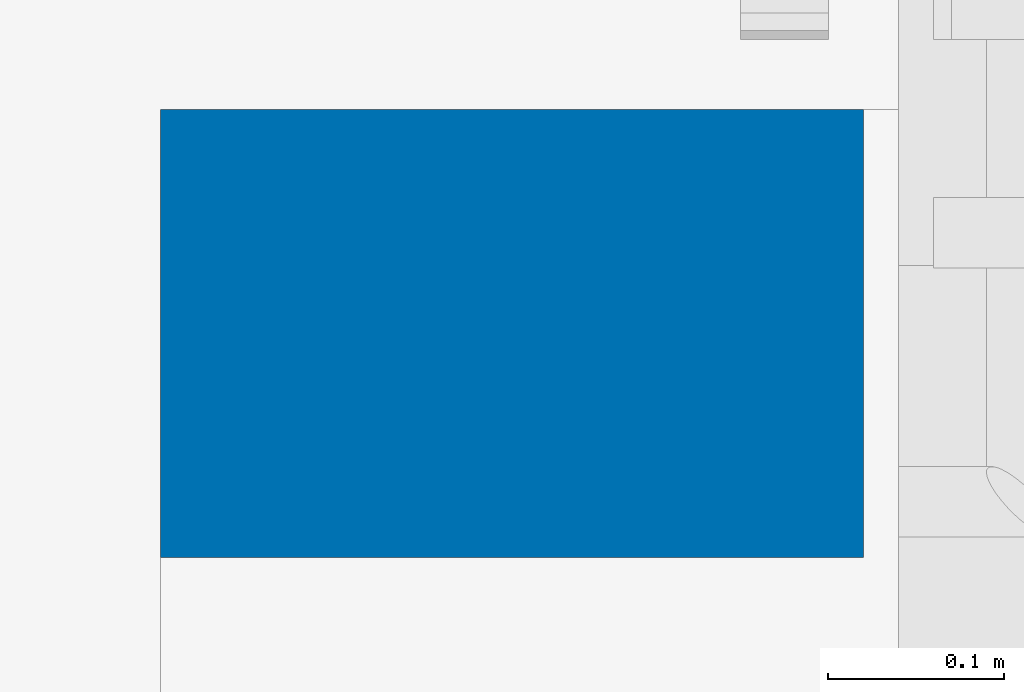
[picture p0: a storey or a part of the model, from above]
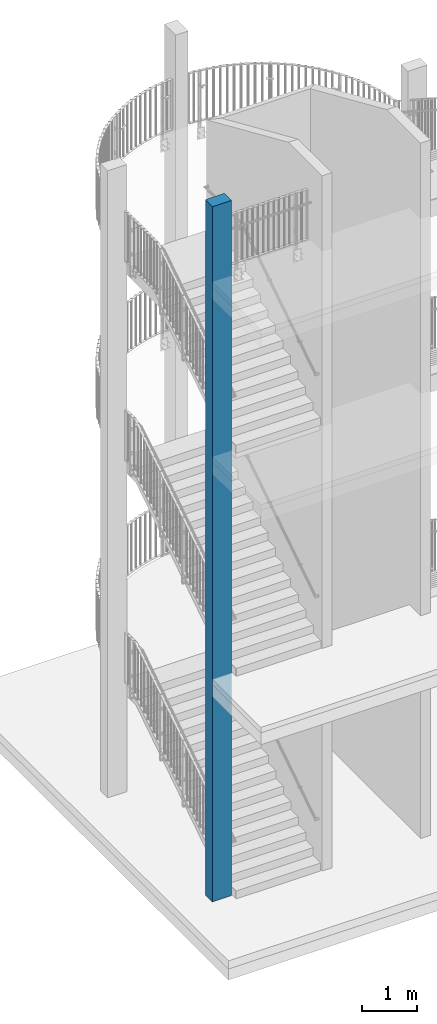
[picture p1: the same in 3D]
Properties of the parts of a building model (IFC2X3)

# File
Description: ViewDefinition[CoordinationView_V2.0]
File name: Treppenhausgel?nder TZ Dresden_ifc2x3.ifc
Time: 2026-07-12T18:13:56
Written by: IFC Toolkit 2.0.26.0
Made in: Advance Steel 2024

# IfcBuildingStorey, Default Storey
In: Struktur 1
Elevation: 0 mm

# IfcBeam: - (91)
In: Default Storey
Material: S235JR
Name | Description = Section | SectionFamily
74 x - | RD12 | Round nach DIN
17 x - | FL50X10 | Flat nach DIN

# IfcBeam: Column
In: Default Storey
Material: C20/25
Pset_BeamCommon - Reference: nicht definiert; Span: 3520 mm; Slope: 0 deg; IsExternal: no; LoadBearing: no

# IfcBeam: Gel?nder (11)
In: Default Storey
Description: FL50X10; Material: S235JR
Pset_BeamCommon - Slope: 0 deg; IsExternal: no; LoadBearing: no
ProfileProperties - SectionFamily: Flat nach DIN; Section: FL50X10
Name | Reference | Span (mm)
Gel?nder | 117 | 312.5
Gel?nder | 76 | 697.496
Gel?nder | 111 | 209.996
Gel?nder | 102 | 214.996
2 x Gel?nder | 66 | 232.5
Gel?nder | 118 | 1225
Gel?nder | 115 | 960.496
2 x Gel?nder | 74 | 177.5
Gel?nder | 99 | 187.5

# IfcBeam: Girder (31)
In: Default Storey
Description: RD40; Material: Buche
Pset_BeamCommon - Slope: 0 deg; IsExternal: no; LoadBearing: no
ProfileProperties - SectionFamily: Round nach DIN; Section: RD40
Name | Reference | Span (mm)
Girder | 7 | 89.6687
Girder | 7 | 89.6743
Girder | 7 | 89.6653
Girder | 23 | 1304.99
Girder | 25 | 489.995
Girder | 26 | 494.994
3 x Girder | 2 | 89.9986
Girder | 41 | 1368
2 x Girder | 4 | 79.6687
Girder | 4 | 79.6743
Girder | 4 | 79.6653
Girder | 45 | 559.998
Girder | 8 | 574.999
Girder | 46 | 1389.99
Girder | 8 | 574.995
Girder | 47 | 579.994
6 x Girder | 1 | 79.9986
Girder | 4 | 79.6709
Girder | 4 | 79.6681
Girder | 59 | 1720
Girder | 12 | 539.999
Girder | 13 | 555
Girder | 11 | 1348

# IfcColumn: - (456)
In: Default Storey
Material: S235JR
Name | Description = Section | SectionFamily
330 x - | RD10 | Round nach DIN
112 x - | FL50X15 | Flat nach DIN
14 x - | FL50X10 | Flat nach DIN

# IfcColumn: Column (5)
In: Default Storey
Material: C20/25
Pset_ColumnCommon - Reference: nicht definiert; Slope: 0 deg; IsExternal: no; LoadBearing: no

# IfcMechanicalFastener: - (199)
In: Default Storey
Name | NominalDiameter (mm) | NominalLength (mm)
50 x  | 12 | 120
99 x  | 8 | 60
50 x  | 12 | 65

# IfcMember: - (29)
In: Default Storey
Description: FL50X10; Material: S235JR
ProfileProperties - SectionFamily: Flat nach DIN; Section: FL50X10

# IfcMember: Gel?nder (22)
In: Default Storey
Description: FL50X10; Material: S235JR
Pset_MemberCommon - Slope: 0 deg; IsExternal: no; LoadBearing: no
ProfileProperties - SectionFamily: Flat nach DIN; Section: FL50X10
Name | Reference | Span (mm)
Gel?nder | 110 | 1275.33
Gel?nder | 68 | 1274.68
Gel?nder | 109 | 959.605
Gel?nder | 108 | 1275.33
Gel?nder | 107 | 163.817
Gel?nder | 73 | 959.118
Gel?nder | 101 | 1274.68
Gel?nder | 100 | 163.735
Gel?nder | 72 | 959.507
Gel?nder | 75 | 1275.2
Gel?nder | 116 | 163.801
Gel?nder | 114 | 953.551
Gel?nder | 105 | 952.585
Gel?nder | 106 | 1092.42
Gel?nder | 97 | 954.135
Gel?nder | 98 | 1088.24
Gel?nder | 96 | 1275.98
Gel?nder | 95 | 318.861
Gel?nder | 104 | 1285.82
Gel?nder | 103 | 318.351
Gel?nder | 113 | 1275.2
Gel?nder | 112 | 324.625

# IfcMember: Girder (12)
In: Default Storey
Description: RD40; Material: Buche
Pset_MemberCommon - Slope: 0 deg; IsExternal: no; LoadBearing: no
ProfileProperties - SectionFamily: Round nach DIN; Section: RD40
Name | Reference | Span (mm)
Girder | 27 | 3122.23
Girder | 28 | 4093.55
Girder | 29 | 4085.53
Girder | 42 | 3168.44
Girder | 43 | 4126.87
Girder | 44 | 4115.61
Girder | 48 | 3142.23
Girder | 49 | 4113.55
Girder | 50 | 4105.53
Girder | 14 | 3071
Girder | 15 | 4018.13
Girder | 16 | 4029.52

# IfcPlate: - (30)
In: Default Storey
Description: -; Material: S235JR 10 mm
Pset_PlateCommon - IsExternal: no; LoadBearing: no
Name | Reference
6 x - | 393
18 x - | 392
6 x - | 394

# IfcPlate: Girder (306)
In: Default Storey
Description: -
Pset_PlateCommon - IsExternal: no; LoadBearing: no
Name | Material | Reference
3 x Girder | S235JR 10 mm | 122
12 x Girder | S235JR 10 mm | 119
3 x Girder | S235JR 10 mm | 121
26 x Girder | S235JR 15 mm | 128
49 x Girder | S235JR 15 mm | 396
49 x Girder | S235JR 15 mm | 131
21 x Girder | S235JR 15 mm | 132
71 x Girder | S235JR 10 mm | 402
3 x Girder | S235JR 15 mm | 136
3 x Girder | S235JR 10 mm | 403
23 x Girder | S235JR 15 mm | 129
6 x Girder | S235JR 15 mm | 135
20 x Girder | S235JR 15 mm | 133
Girder | S235JR 15 mm | 397
Girder | S235JR 15 mm | 130
3 x Girder | S235JR 10 mm | 395
3 x Girder | S235JR 10 mm | 127
3 x Girder | S235JR 10 mm | 123
3 x Girder | S235JR 10 mm | 120
3 x Girder | S235JR 10 mm | 125

# IfcSlab: - (14)
In: Default Storey
Description: -
Pset_SlabCommon - Reference: nicht definiert; IsExternal: no; LoadBearing: no; Combustible: no; Compartmentation: no; PitchAngle: 0 deg
Name | Material
6 x - | C25/30 120 mm
6 x - | C25/30 260 mm
- | C25/30 180 mm
- | C25/30 240 mm

# IfcWall: - (15)
In: Default Storey
Description: -
Pset_WallCommon - Reference: nicht definiert; Combustible: no; IsExternal: no; ExtendToStructure: no; LoadBearing: no; Compartmentation: no
Name | Material
12 x - | C25/30 1760 mm
3 x - | C25/30 200 mm
